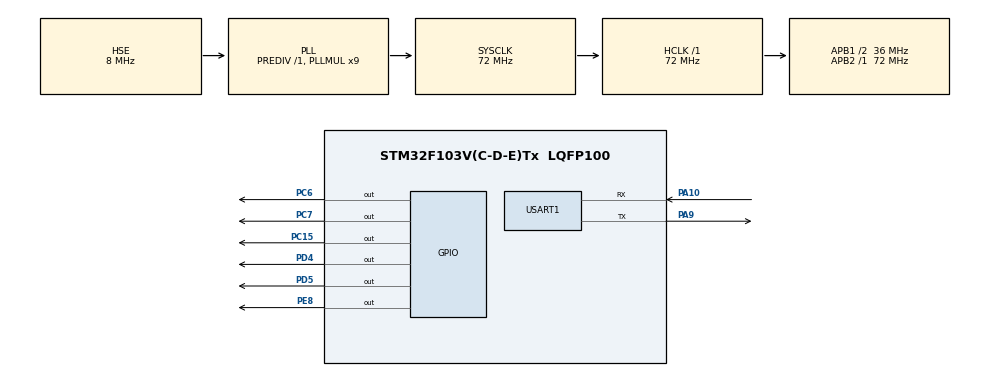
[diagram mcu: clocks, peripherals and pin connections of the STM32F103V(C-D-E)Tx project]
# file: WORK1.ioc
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Mcu.Family=STM32F1
Mcu.Name=STM32F103V(C-D-E)Tx
Mcu.Package=LQFP100
NVIC.PriorityGroup=NVIC_PRIORITYGROUP_4
NVIC.USART1_IRQn=true\:0\:0\:false\:false\:true\:true
OSC_IN.Mode=HSE-External-Oscillator
OSC_IN.Signal=RCC_OSC_IN
OSC_OUT.Mode=HSE-External-Oscillator
OSC_OUT.Signal=RCC_OSC_OUT
PA10.Mode=Asynchronous
PA10.Signal=USART1_RX
PA9.Mode=Asynchronous
PA9.Signal=USART1_TX
PC15-OSC32_OUT.Signal=GPIO_Output
PC6.Signal=GPIO_Output
PC7.Signal=GPIO_Output
PD4.Signal=GPIO_Output
PD5.Signal=GPIO_Output
PE8.Signal=GPIO_Output
ProjectManager.HeapSize=0x200
ProjectManager.StackSize=0x400
ProjectManager.TargetToolchain=EWARM
RCC.AHBFreq_Value=72000000
RCC.APB1CLKDivider=RCC_HCLK_DIV2
RCC.APB1Freq_Value=36000000
RCC.APB1TimFreq_Value=72000000
RCC.APB2Freq_Value=72000000
RCC.APB2TimFreq_Value=72000000
RCC.HCLKFreq_Value=72000000
RCC.PLLMUL=RCC_PLL_MUL9
RCC.PLLSourceVirtual=RCC_PLLSOURCE_HSE
RCC.SYSCLKFreq_VALUE=72000000
RCC.SYSCLKSource=RCC_SYSCLKSOURCE_PLLCLK
RCC.USBFreq_Value=72000000
USART1.VirtualMode=VM_ASYNC
VP_SYS_VS_ND.Mode=No_Debug
board=custom

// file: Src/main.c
#include "main.h"
#include "stm32f1xx_hal.h"

UART_HandleTypeDef huart1;

/* USER CODE BEGIN PV */
/* Private variables ---------------------------------------------------------*/

/* USER CODE END PV */

void SystemClock_Config(void);
static void MX_GPIO_Init(void);
static void MX_USART1_UART_Init(void);

/* USER CODE BEGIN PFP */
/* Private function prototypes -----------------------------------------------*/

/* USER CODE END PFP */

/* USER CODE BEGIN 0 */

int fputc(int ch, FILE *f)
{
  uint8_t temp[1]={ch};
  HAL_UART_Transmit(&huart1, temp, 1, 2);
  return(ch);
}
/* USER CODE END 0 */

int main(void)
{
  HAL_Init();
SystemClock_Config();
  MX_GPIO_Init();
  MX_USART1_UART_Init();
  while (1)
  {
    if(!(HAL_GPIO_ReadPin(GPIOC, GPIO_PIN_0))){
      HAL_UART_Transmit(&huart1, "R" , 1 , 2);
    }
    if(!(HAL_GPIO_ReadPin(GPIOC, GPIO_PIN_1))){
      HAL_UART_Transmit(&huart1, "G" , 1 , 2);
    }
    if(!(HAL_GPIO_ReadPin(GPIOC, GPIO_PIN_2))){
      HAL_UART_Transmit(&huart1, "B" , 1 , 2);
    }

    HAL_Delay(200);
  }

}

void SystemClock_Config(void)
{

  RCC_OscInitTypeDef RCC_OscInitStruct;
  RCC_ClkInitTypeDef RCC_ClkInitStruct;

    /**Initializes the CPU, AHB and APB busses clocks
    */
  RCC_OscInitStruct.OscillatorType = RCC_OSCILLATORTYPE_HSE;
  RCC_OscInitStruct.HSEState = RCC_HSE_ON;
  RCC_OscInitStruct.HSEPredivValue = RCC_HSE_PREDIV_DIV1;
  RCC_OscInitStruct.HSIState = RCC_HSI_ON;
  RCC_OscInitStruct.PLL.PLLState = RCC_PLL_ON;
  RCC_OscInitStruct.PLL.PLLSource = RCC_PLLSOURCE_HSE;
  RCC_OscInitStruct.PLL.PLLMUL = RCC_PLL_MUL9;
  if (HAL_RCC_OscConfig(&RCC_OscInitStruct) != HAL_OK)
  {
    Error_Handler(__FILE_, _LINE_);
  }

    /**Initializes the CPU, AHB and APB busses clocks
    */
  RCC_ClkInitStruct.ClockType = RCC_CLOCKTYPE_HCLK|RCC_CLOCKTYPE_SYSCLK
                              |RCC_CLOCKTYPE_PCLK1|RCC_CLOCKTYPE_PCLK2;
  RCC_ClkInitStruct.SYSCLKSource = RCC_SYSCLKSOURCE_PLLCLK;
  RCC_ClkInitStruct.AHBCLKDivider = RCC_SYSCLK_DIV1;
  RCC_ClkInitStruct.APB1CLKDivider = RCC_HCLK_DIV2;
  RCC_ClkInitStruct.APB2CLKDivider = RCC_HCLK_DIV1;

  if (HAL_RCC_ClockConfig(&RCC_ClkInitStruct, FLASH_LATENCY_2) != HAL_OK)
  {
    Error_Handler(__FILE_, _LINE_);
  }

    /**Configure the Systick interrupt time
    */
  HAL_SYSTICK_Config(HAL_RCC_GetHCLKFreq()/1000);

    /**Configure the Systick
    */
  HAL_SYSTICK_CLKSourceConfig(SYSTICK_CLKSOURCE_HCLK);

  /* SysTick_IRQn interrupt configuration */
  HAL_NVIC_SetPriority(SysTick_IRQn, 0, 0);
}

/* USART1 init function */
static void MX_USART1_UART_Init(void)
{

  huart1.Instance = USART1;
  huart1.Init.BaudRate = 115200;
  huart1.Init.WordLength = UART_WORDLENGTH_8B;
  huart1.Init.StopBits = UART_STOPBITS_1;
  huart1.Init.Parity = UART_PARITY_NONE;
  huart1.Init.Mode = UART_MODE_TX_RX;
  huart1.Init.HwFlowCtl = UART_HWCONTROL_NONE;
  huart1.Init.OverSampling = UART_OVERSAMPLING_16;
  if (HAL_UART_Init(&huart1) != HAL_OK)
  {
    Error_Handler(__FILE_, _LINE_);
  }

}

/** Configure pins as
        * Analog
        * Input
        * Output
        * EVENT_OUT
        * EXTI
*/
static void MX_GPIO_Init(void)
{

  GPIO_InitTypeDef GPIO_InitStruct;

  /* GPIO Ports Clock Enable */
  __HAL_RCC_GPIOC_CLK_ENABLE();
  __HAL_RCC_GPIOA_CLK_ENABLE();

  /*Configure GPIO pins : PC0 PC1 PC2 */
  GPIO_InitStruct.Pin = GPIO_PIN_0|GPIO_PIN_1|GPIO_PIN_2;
  GPIO_InitStruct.Mode = GPIO_MODE_INPUT;
  GPIO_InitStruct.Pull = GPIO_NOPULL;
  HAL_GPIO_Init(GPIOC, &GPIO_InitStruct);

}

void _Error_Handler(char *file, int line)
{
  while(1)
  {
  }
}

/************************ (C) COPYRIGHT STMicroelectronics *****END OF FILE****/
